VERSION 5.7 ;
  NOWIREEXTENSIONATPIN ON ;
  DIVIDERCHAR "/" ;
  BUSBITCHARS "[]" ;
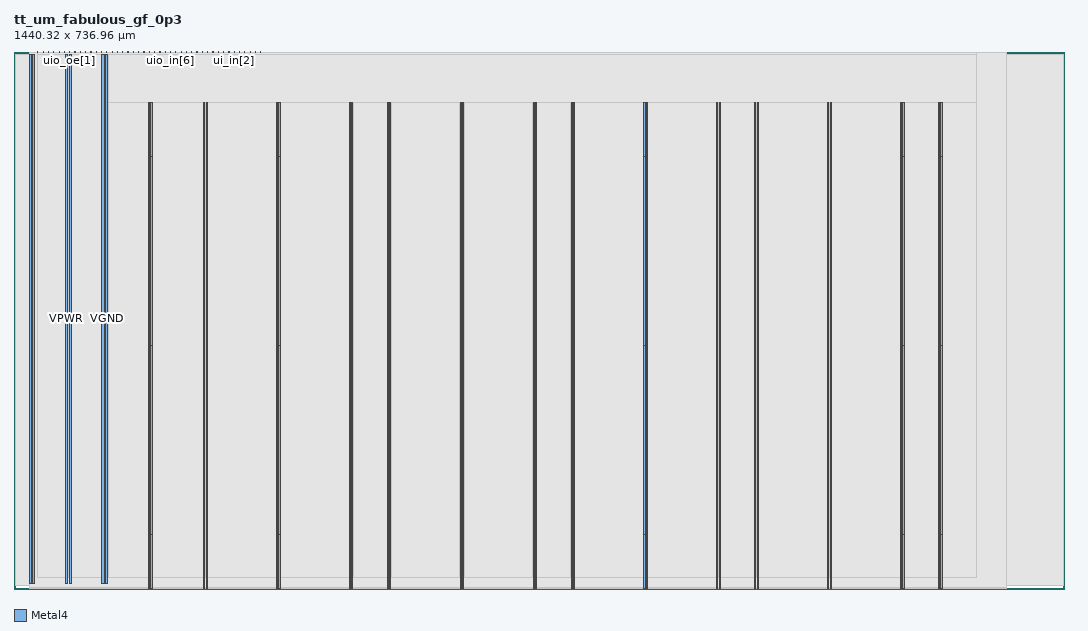
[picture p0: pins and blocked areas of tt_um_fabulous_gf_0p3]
MACRO tt_um_fabulous_gf_0p3
  CLASS BLOCK ;
  FOREIGN tt_um_fabulous_gf_0p3 ;
  ORIGIN 0.000 0.000 ;
  SIZE 1440.320 BY 736.960 ;
  PIN VGND
    DIRECTION INOUT ;
    USE GROUND ;
    PORT
      LAYER Metal4 ;
        RECT 187.780 592.600 189.380 667.080 ;
    END
    PORT
      LAYER Metal4 ;
        RECT 187.780 333.880 189.380 592.600 ;
    END
    PORT
      LAYER Metal4 ;
        RECT 187.780 75.160 189.380 333.880 ;
    END
    PORT
      LAYER Metal4 ;
        RECT 187.780 0.680 189.380 75.160 ;
    END
    PORT
      LAYER Metal4 ;
        RECT 263.380 592.600 264.980 667.080 ;
    END
    PORT
      LAYER Metal4 ;
        RECT 363.380 592.600 364.980 667.080 ;
    END
    PORT
      LAYER Metal4 ;
        RECT 463.380 592.600 464.980 667.080 ;
    END
    PORT
      LAYER Metal4 ;
        RECT 263.380 333.880 264.980 592.600 ;
    END
    PORT
      LAYER Metal4 ;
        RECT 363.380 333.880 364.980 592.600 ;
    END
    PORT
      LAYER Metal4 ;
        RECT 463.380 333.880 464.980 592.600 ;
    END
    PORT
      LAYER Metal4 ;
        RECT 263.380 75.160 264.980 333.880 ;
    END
    PORT
      LAYER Metal4 ;
        RECT 363.380 75.160 364.980 333.880 ;
    END
    PORT
      LAYER Metal4 ;
        RECT 463.380 75.160 464.980 333.880 ;
    END
    PORT
      LAYER Metal4 ;
        RECT 263.380 0.680 264.980 75.160 ;
    END
    PORT
      LAYER Metal4 ;
        RECT 363.380 0.680 364.980 75.160 ;
    END
    PORT
      LAYER Metal4 ;
        RECT 463.380 0.680 464.980 75.160 ;
    END
    PORT
      LAYER Metal4 ;
        RECT 515.380 592.600 516.980 667.080 ;
    END
    PORT
      LAYER Metal4 ;
        RECT 615.380 592.600 616.980 667.080 ;
    END
    PORT
      LAYER Metal4 ;
        RECT 715.380 592.600 716.980 667.080 ;
    END
    PORT
      LAYER Metal4 ;
        RECT 515.380 333.880 516.980 592.600 ;
    END
    PORT
      LAYER Metal4 ;
        RECT 615.380 333.880 616.980 592.600 ;
    END
    PORT
      LAYER Metal4 ;
        RECT 715.380 333.880 716.980 592.600 ;
    END
    PORT
      LAYER Metal4 ;
        RECT 515.380 75.160 516.980 333.880 ;
    END
    PORT
      LAYER Metal4 ;
        RECT 615.380 75.160 616.980 333.880 ;
    END
    PORT
      LAYER Metal4 ;
        RECT 715.380 75.160 716.980 333.880 ;
    END
    PORT
      LAYER Metal4 ;
        RECT 515.380 0.680 516.980 75.160 ;
    END
    PORT
      LAYER Metal4 ;
        RECT 615.380 0.680 616.980 75.160 ;
    END
    PORT
      LAYER Metal4 ;
        RECT 715.380 0.680 716.980 75.160 ;
    END
    PORT
      LAYER Metal4 ;
        RECT 767.380 592.600 768.980 667.080 ;
    END
    PORT
      LAYER Metal4 ;
        RECT 867.380 592.600 868.980 667.080 ;
    END
    PORT
      LAYER Metal4 ;
        RECT 967.380 592.600 968.980 667.080 ;
    END
    PORT
      LAYER Metal4 ;
        RECT 767.380 333.880 768.980 592.600 ;
    END
    PORT
      LAYER Metal4 ;
        RECT 867.380 333.880 868.980 592.600 ;
    END
    PORT
      LAYER Metal4 ;
        RECT 967.380 333.880 968.980 592.600 ;
    END
    PORT
      LAYER Metal4 ;
        RECT 767.380 75.160 768.980 333.880 ;
    END
    PORT
      LAYER Metal4 ;
        RECT 867.380 75.160 868.980 333.880 ;
    END
    PORT
      LAYER Metal4 ;
        RECT 967.380 75.160 968.980 333.880 ;
    END
    PORT
      LAYER Metal4 ;
        RECT 767.380 0.680 768.980 75.160 ;
    END
    PORT
      LAYER Metal4 ;
        RECT 867.380 0.680 868.980 75.160 ;
    END
    PORT
      LAYER Metal4 ;
        RECT 967.380 0.680 968.980 75.160 ;
    END
    PORT
      LAYER Metal4 ;
        RECT 1019.380 592.600 1020.980 667.080 ;
    END
    PORT
      LAYER Metal4 ;
        RECT 1119.380 592.600 1120.980 667.080 ;
    END
    PORT
      LAYER Metal4 ;
        RECT 1219.380 592.600 1220.980 667.080 ;
    END
    PORT
      LAYER Metal4 ;
        RECT 1019.380 333.880 1020.980 592.600 ;
    END
    PORT
      LAYER Metal4 ;
        RECT 1119.380 333.880 1120.980 592.600 ;
    END
    PORT
      LAYER Metal4 ;
        RECT 1219.380 333.880 1220.980 592.600 ;
    END
    PORT
      LAYER Metal4 ;
        RECT 1019.380 75.160 1020.980 333.880 ;
    END
    PORT
      LAYER Metal4 ;
        RECT 1119.380 75.160 1120.980 333.880 ;
    END
    PORT
      LAYER Metal4 ;
        RECT 1219.380 75.160 1220.980 333.880 ;
    END
    PORT
      LAYER Metal4 ;
        RECT 1019.380 0.680 1020.980 75.160 ;
    END
    PORT
      LAYER Metal4 ;
        RECT 1119.380 0.680 1120.980 75.160 ;
    END
    PORT
      LAYER Metal4 ;
        RECT 1219.380 0.680 1220.980 75.160 ;
    END
    PORT
      LAYER Metal4 ;
        RECT 1271.380 592.600 1272.980 667.080 ;
    END
    PORT
      LAYER Metal4 ;
        RECT 1271.380 333.880 1272.980 592.600 ;
    END
    PORT
      LAYER Metal4 ;
        RECT 1271.380 75.160 1272.980 333.880 ;
    END
    PORT
      LAYER Metal4 ;
        RECT 1271.380 0.680 1272.980 75.160 ;
    END
    PORT
      LAYER Metal4 ;
        RECT 25.540 7.540 28.740 733.340 ;
    END
    PORT
      LAYER Metal4 ;
        RECT 75.540 7.540 78.740 733.340 ;
    END
    PORT
      LAYER Metal4 ;
        RECT 125.540 7.540 128.740 733.340 ;
    END
  END VGND
  PIN VPWR
    DIRECTION INOUT ;
    USE POWER ;
    PORT
      LAYER Metal4 ;
        RECT 184.480 592.600 186.080 667.080 ;
    END
    PORT
      LAYER Metal4 ;
        RECT 184.480 333.880 186.080 592.600 ;
    END
    PORT
      LAYER Metal4 ;
        RECT 184.480 75.160 186.080 333.880 ;
    END
    PORT
      LAYER Metal4 ;
        RECT 184.480 0.680 186.080 75.160 ;
    END
    PORT
      LAYER Metal4 ;
        RECT 260.080 592.600 261.680 667.080 ;
    END
    PORT
      LAYER Metal4 ;
        RECT 360.080 592.600 361.680 667.080 ;
    END
    PORT
      LAYER Metal4 ;
        RECT 460.080 592.600 461.680 667.080 ;
    END
    PORT
      LAYER Metal4 ;
        RECT 260.080 333.880 261.680 592.600 ;
    END
    PORT
      LAYER Metal4 ;
        RECT 360.080 333.880 361.680 592.600 ;
    END
    PORT
      LAYER Metal4 ;
        RECT 460.080 333.880 461.680 592.600 ;
    END
    PORT
      LAYER Metal4 ;
        RECT 260.080 75.160 261.680 333.880 ;
    END
    PORT
      LAYER Metal4 ;
        RECT 360.080 75.160 361.680 333.880 ;
    END
    PORT
      LAYER Metal4 ;
        RECT 460.080 75.160 461.680 333.880 ;
    END
    PORT
      LAYER Metal4 ;
        RECT 260.080 0.680 261.680 75.160 ;
    END
    PORT
      LAYER Metal4 ;
        RECT 360.080 0.680 361.680 75.160 ;
    END
    PORT
      LAYER Metal4 ;
        RECT 460.080 0.680 461.680 75.160 ;
    END
    PORT
      LAYER Metal4 ;
        RECT 512.080 592.600 513.680 667.080 ;
    END
    PORT
      LAYER Metal4 ;
        RECT 612.080 592.600 613.680 667.080 ;
    END
    PORT
      LAYER Metal4 ;
        RECT 712.080 592.600 713.680 667.080 ;
    END
    PORT
      LAYER Metal4 ;
        RECT 512.080 333.880 513.680 592.600 ;
    END
    PORT
      LAYER Metal4 ;
        RECT 612.080 333.880 613.680 592.600 ;
    END
    PORT
      LAYER Metal4 ;
        RECT 712.080 333.880 713.680 592.600 ;
    END
    PORT
      LAYER Metal4 ;
        RECT 512.080 75.160 513.680 333.880 ;
    END
    PORT
      LAYER Metal4 ;
        RECT 612.080 75.160 613.680 333.880 ;
    END
    PORT
      LAYER Metal4 ;
        RECT 712.080 75.160 713.680 333.880 ;
    END
    PORT
      LAYER Metal4 ;
        RECT 512.080 0.680 513.680 75.160 ;
    END
    PORT
      LAYER Metal4 ;
        RECT 612.080 0.680 613.680 75.160 ;
    END
    PORT
      LAYER Metal4 ;
        RECT 712.080 0.680 713.680 75.160 ;
    END
    PORT
      LAYER Metal4 ;
        RECT 764.080 592.600 765.680 667.080 ;
    END
    PORT
      LAYER Metal4 ;
        RECT 864.080 592.600 865.680 667.080 ;
    END
    PORT
      LAYER Metal4 ;
        RECT 964.080 592.600 965.680 667.080 ;
    END
    PORT
      LAYER Metal4 ;
        RECT 764.080 333.880 765.680 592.600 ;
    END
    PORT
      LAYER Metal4 ;
        RECT 864.080 333.880 865.680 592.600 ;
    END
    PORT
      LAYER Metal4 ;
        RECT 964.080 333.880 965.680 592.600 ;
    END
    PORT
      LAYER Metal4 ;
        RECT 764.080 75.160 765.680 333.880 ;
    END
    PORT
      LAYER Metal4 ;
        RECT 864.080 75.160 865.680 333.880 ;
    END
    PORT
      LAYER Metal4 ;
        RECT 964.080 75.160 965.680 333.880 ;
    END
    PORT
      LAYER Metal4 ;
        RECT 764.080 0.680 765.680 75.160 ;
    END
    PORT
      LAYER Metal4 ;
        RECT 864.080 0.680 865.680 75.160 ;
    END
    PORT
      LAYER Metal4 ;
        RECT 964.080 0.680 965.680 75.160 ;
    END
    PORT
      LAYER Metal4 ;
        RECT 1016.080 592.600 1017.680 667.080 ;
    END
    PORT
      LAYER Metal4 ;
        RECT 1116.080 592.600 1117.680 667.080 ;
    END
    PORT
      LAYER Metal4 ;
        RECT 1216.080 592.600 1217.680 667.080 ;
    END
    PORT
      LAYER Metal4 ;
        RECT 1016.080 333.880 1017.680 592.600 ;
    END
    PORT
      LAYER Metal4 ;
        RECT 1116.080 333.880 1117.680 592.600 ;
    END
    PORT
      LAYER Metal4 ;
        RECT 1216.080 333.880 1217.680 592.600 ;
    END
    PORT
      LAYER Metal4 ;
        RECT 1016.080 75.160 1017.680 333.880 ;
    END
    PORT
      LAYER Metal4 ;
        RECT 1116.080 75.160 1117.680 333.880 ;
    END
    PORT
      LAYER Metal4 ;
        RECT 1216.080 75.160 1217.680 333.880 ;
    END
    PORT
      LAYER Metal4 ;
        RECT 1016.080 0.680 1017.680 75.160 ;
    END
    PORT
      LAYER Metal4 ;
        RECT 1116.080 0.680 1117.680 75.160 ;
    END
    PORT
      LAYER Metal4 ;
        RECT 1216.080 0.680 1217.680 75.160 ;
    END
    PORT
      LAYER Metal4 ;
        RECT 1268.080 592.600 1269.680 667.080 ;
    END
    PORT
      LAYER Metal4 ;
        RECT 1268.080 333.880 1269.680 592.600 ;
    END
    PORT
      LAYER Metal4 ;
        RECT 1268.080 75.160 1269.680 333.880 ;
    END
    PORT
      LAYER Metal4 ;
        RECT 1268.080 0.680 1269.680 75.160 ;
    END
    PORT
      LAYER Metal4 ;
        RECT 20.640 7.540 23.840 733.340 ;
    END
    PORT
      LAYER Metal4 ;
        RECT 70.640 7.540 73.840 733.340 ;
    END
    PORT
      LAYER Metal4 ;
        RECT 120.640 7.540 123.840 733.340 ;
    END
  END VPWR
  PIN clk
    DIRECTION INPUT ;
    USE SIGNAL ;
    ANTENNAGATEAREA 9.476000 ;
    ANTENNADIFFAREA 0.820800 ;
    PORT
      LAYER Metal4 ;
        RECT 331.090 735.960 331.390 736.960 ;
    END
  END clk
  PIN ena
    DIRECTION INPUT ;
    USE SIGNAL ;
    PORT
      LAYER Metal4 ;
        RECT 338.370 735.960 338.670 736.960 ;
    END
  END ena
  PIN rst_n
    DIRECTION INPUT ;
    USE SIGNAL ;
    ANTENNAGATEAREA 0.396000 ;
    ANTENNADIFFAREA 0.410400 ;
    PORT
      LAYER Metal4 ;
        RECT 323.810 735.960 324.110 736.960 ;
    END
  END rst_n
  PIN ui_in[0]
    DIRECTION INPUT ;
    USE SIGNAL ;
    ANTENNAGATEAREA 0.396000 ;
    ANTENNADIFFAREA 0.410400 ;
    PORT
      LAYER Metal4 ;
        RECT 316.530 735.960 316.830 736.960 ;
    END
  END ui_in[0]
  PIN ui_in[1]
    DIRECTION INPUT ;
    USE SIGNAL ;
    ANTENNAGATEAREA 0.396000 ;
    ANTENNADIFFAREA 0.410400 ;
    PORT
      LAYER Metal4 ;
        RECT 309.250 735.960 309.550 736.960 ;
    END
  END ui_in[1]
  PIN ui_in[2]
    DIRECTION INPUT ;
    USE SIGNAL ;
    ANTENNAGATEAREA 1.498000 ;
    ANTENNADIFFAREA 0.410400 ;
    PORT
      LAYER Metal4 ;
        RECT 301.970 735.960 302.270 736.960 ;
    END
  END ui_in[2]
  PIN ui_in[3]
    DIRECTION INPUT ;
    USE SIGNAL ;
    ANTENNAGATEAREA 1.498000 ;
    ANTENNADIFFAREA 0.410400 ;
    PORT
      LAYER Metal4 ;
        RECT 294.690 735.960 294.990 736.960 ;
    END
  END ui_in[3]
  PIN ui_in[4]
    DIRECTION INPUT ;
    USE SIGNAL ;
    ANTENNAGATEAREA 1.498000 ;
    ANTENNADIFFAREA 0.410400 ;
    PORT
      LAYER Metal4 ;
        RECT 287.410 735.960 287.710 736.960 ;
    END
  END ui_in[4]
  PIN ui_in[5]
    DIRECTION INPUT ;
    USE SIGNAL ;
    ANTENNAGATEAREA 1.498000 ;
    ANTENNADIFFAREA 0.410400 ;
    PORT
      LAYER Metal4 ;
        RECT 280.130 735.960 280.430 736.960 ;
    END
  END ui_in[5]
  PIN ui_in[6]
    DIRECTION INPUT ;
    USE SIGNAL ;
    ANTENNAGATEAREA 1.498000 ;
    ANTENNADIFFAREA 0.410400 ;
    PORT
      LAYER Metal4 ;
        RECT 272.850 735.960 273.150 736.960 ;
    END
  END ui_in[6]
  PIN ui_in[7]
    DIRECTION INPUT ;
    USE SIGNAL ;
    ANTENNAGATEAREA 1.498000 ;
    ANTENNADIFFAREA 0.410400 ;
    PORT
      LAYER Metal4 ;
        RECT 265.570 735.960 265.870 736.960 ;
    END
  END ui_in[7]
  PIN uio_in[0]
    DIRECTION INPUT ;
    USE SIGNAL ;
    ANTENNAGATEAREA 1.498000 ;
    ANTENNADIFFAREA 0.410400 ;
    PORT
      LAYER Metal4 ;
        RECT 258.290 735.960 258.590 736.960 ;
    END
  END uio_in[0]
  PIN uio_in[1]
    DIRECTION INPUT ;
    USE SIGNAL ;
    ANTENNAGATEAREA 1.498000 ;
    ANTENNADIFFAREA 0.410400 ;
    PORT
      LAYER Metal4 ;
        RECT 251.010 735.960 251.310 736.960 ;
    END
  END uio_in[1]
  PIN uio_in[2]
    DIRECTION INPUT ;
    USE SIGNAL ;
    ANTENNAGATEAREA 2.597500 ;
    ANTENNADIFFAREA 0.410400 ;
    PORT
      LAYER Metal4 ;
        RECT 243.730 735.960 244.030 736.960 ;
    END
  END uio_in[2]
  PIN uio_in[3]
    DIRECTION INPUT ;
    USE SIGNAL ;
    ANTENNAGATEAREA 1.498000 ;
    ANTENNADIFFAREA 0.410400 ;
    PORT
      LAYER Metal4 ;
        RECT 236.450 735.960 236.750 736.960 ;
    END
  END uio_in[3]
  PIN uio_in[4]
    DIRECTION INPUT ;
    USE SIGNAL ;
    ANTENNAGATEAREA 1.498000 ;
    ANTENNADIFFAREA 0.410400 ;
    PORT
      LAYER Metal4 ;
        RECT 229.170 735.960 229.470 736.960 ;
    END
  END uio_in[4]
  PIN uio_in[5]
    DIRECTION INPUT ;
    USE SIGNAL ;
    ANTENNAGATEAREA 1.498000 ;
    ANTENNADIFFAREA 0.410400 ;
    PORT
      LAYER Metal4 ;
        RECT 221.890 735.960 222.190 736.960 ;
    END
  END uio_in[5]
  PIN uio_in[6]
    DIRECTION INPUT ;
    USE SIGNAL ;
    ANTENNAGATEAREA 2.597500 ;
    ANTENNADIFFAREA 0.410400 ;
    PORT
      LAYER Metal4 ;
        RECT 214.610 735.960 214.910 736.960 ;
    END
  END uio_in[6]
  PIN uio_in[7]
    DIRECTION INPUT ;
    USE SIGNAL ;
    ANTENNAGATEAREA 1.498000 ;
    ANTENNADIFFAREA 0.820800 ;
    PORT
      LAYER Metal4 ;
        RECT 207.330 735.960 207.630 736.960 ;
    END
  END uio_in[7]
  PIN uio_oe[0]
    DIRECTION OUTPUT ;
    USE SIGNAL ;
    ANTENNADIFFAREA 1.308000 ;
    PORT
      LAYER Metal4 ;
        RECT 83.570 735.960 83.870 736.960 ;
    END
  END uio_oe[0]
  PIN uio_oe[1]
    DIRECTION OUTPUT ;
    USE SIGNAL ;
    ANTENNADIFFAREA 1.308000 ;
    PORT
      LAYER Metal4 ;
        RECT 76.290 735.960 76.590 736.960 ;
    END
  END uio_oe[1]
  PIN uio_oe[2]
    DIRECTION OUTPUT ;
    USE SIGNAL ;
    ANTENNADIFFAREA 1.308000 ;
    PORT
      LAYER Metal4 ;
        RECT 69.010 735.960 69.310 736.960 ;
    END
  END uio_oe[2]
  PIN uio_oe[3]
    DIRECTION OUTPUT ;
    USE SIGNAL ;
    ANTENNADIFFAREA 1.308000 ;
    PORT
      LAYER Metal4 ;
        RECT 61.730 735.960 62.030 736.960 ;
    END
  END uio_oe[3]
  PIN uio_oe[4]
    DIRECTION OUTPUT ;
    USE SIGNAL ;
    ANTENNADIFFAREA 1.308000 ;
    PORT
      LAYER Metal4 ;
        RECT 54.450 735.960 54.750 736.960 ;
    END
  END uio_oe[4]
  PIN uio_oe[5]
    DIRECTION OUTPUT ;
    USE SIGNAL ;
    ANTENNADIFFAREA 1.308000 ;
    PORT
      LAYER Metal4 ;
        RECT 47.170 735.960 47.470 736.960 ;
    END
  END uio_oe[5]
  PIN uio_oe[6]
    DIRECTION OUTPUT ;
    USE SIGNAL ;
    ANTENNADIFFAREA 1.308000 ;
    PORT
      LAYER Metal4 ;
        RECT 39.890 735.960 40.190 736.960 ;
    END
  END uio_oe[6]
  PIN uio_oe[7]
    DIRECTION OUTPUT ;
    USE SIGNAL ;
    ANTENNADIFFAREA 1.308000 ;
    PORT
      LAYER Metal4 ;
        RECT 32.610 735.960 32.910 736.960 ;
    END
  END uio_oe[7]
  PIN uio_out[0]
    DIRECTION OUTPUT ;
    USE SIGNAL ;
    ANTENNADIFFAREA 1.308000 ;
    PORT
      LAYER Metal4 ;
        RECT 141.810 735.960 142.110 736.960 ;
    END
  END uio_out[0]
  PIN uio_out[1]
    DIRECTION OUTPUT ;
    USE SIGNAL ;
    ANTENNADIFFAREA 1.308000 ;
    PORT
      LAYER Metal4 ;
        RECT 134.530 735.960 134.830 736.960 ;
    END
  END uio_out[1]
  PIN uio_out[2]
    DIRECTION OUTPUT ;
    USE SIGNAL ;
    ANTENNADIFFAREA 1.308000 ;
    PORT
      LAYER Metal4 ;
        RECT 127.250 735.960 127.550 736.960 ;
    END
  END uio_out[2]
  PIN uio_out[3]
    DIRECTION OUTPUT ;
    USE SIGNAL ;
    ANTENNADIFFAREA 1.308000 ;
    PORT
      LAYER Metal4 ;
        RECT 119.970 735.960 120.270 736.960 ;
    END
  END uio_out[3]
  PIN uio_out[4]
    DIRECTION OUTPUT ;
    USE SIGNAL ;
    ANTENNADIFFAREA 1.308000 ;
    PORT
      LAYER Metal4 ;
        RECT 112.690 735.960 112.990 736.960 ;
    END
  END uio_out[4]
  PIN uio_out[5]
    DIRECTION OUTPUT ;
    USE SIGNAL ;
    ANTENNADIFFAREA 1.308000 ;
    PORT
      LAYER Metal4 ;
        RECT 105.410 735.960 105.710 736.960 ;
    END
  END uio_out[5]
  PIN uio_out[6]
    DIRECTION OUTPUT ;
    USE SIGNAL ;
    ANTENNADIFFAREA 1.308000 ;
    PORT
      LAYER Metal4 ;
        RECT 98.130 735.960 98.430 736.960 ;
    END
  END uio_out[6]
  PIN uio_out[7]
    DIRECTION OUTPUT ;
    USE SIGNAL ;
    ANTENNADIFFAREA 1.308000 ;
    PORT
      LAYER Metal4 ;
        RECT 90.850 735.960 91.150 736.960 ;
    END
  END uio_out[7]
  PIN uo_out[0]
    DIRECTION OUTPUT ;
    USE SIGNAL ;
    ANTENNADIFFAREA 2.776000 ;
    PORT
      LAYER Metal4 ;
        RECT 200.050 735.960 200.350 736.960 ;
    END
  END uo_out[0]
  PIN uo_out[1]
    DIRECTION OUTPUT ;
    USE SIGNAL ;
    ANTENNADIFFAREA 2.776000 ;
    PORT
      LAYER Metal4 ;
        RECT 192.770 735.960 193.070 736.960 ;
    END
  END uo_out[1]
  PIN uo_out[2]
    DIRECTION OUTPUT ;
    USE SIGNAL ;
    ANTENNADIFFAREA 5.141600 ;
    PORT
      LAYER Metal4 ;
        RECT 185.490 735.960 185.790 736.960 ;
    END
  END uo_out[2]
  PIN uo_out[3]
    DIRECTION OUTPUT ;
    USE SIGNAL ;
    ANTENNADIFFAREA 5.141600 ;
    PORT
      LAYER Metal4 ;
        RECT 178.210 735.960 178.510 736.960 ;
    END
  END uo_out[3]
  PIN uo_out[4]
    DIRECTION OUTPUT ;
    USE SIGNAL ;
    ANTENNADIFFAREA 5.141600 ;
    PORT
      LAYER Metal4 ;
        RECT 170.930 735.960 171.230 736.960 ;
    END
  END uo_out[4]
  PIN uo_out[5]
    DIRECTION OUTPUT ;
    USE SIGNAL ;
    ANTENNADIFFAREA 5.141600 ;
    PORT
      LAYER Metal4 ;
        RECT 163.650 735.960 163.950 736.960 ;
    END
  END uo_out[5]
  PIN uo_out[6]
    DIRECTION OUTPUT ;
    USE SIGNAL ;
    ANTENNADIFFAREA 5.141600 ;
    PORT
      LAYER Metal4 ;
        RECT 156.370 735.960 156.670 736.960 ;
    END
  END uo_out[6]
  PIN uo_out[7]
    DIRECTION OUTPUT ;
    USE SIGNAL ;
    ANTENNADIFFAREA 5.141600 ;
    PORT
      LAYER Metal4 ;
        RECT 149.090 735.960 149.390 736.960 ;
    END
  END uo_out[7]
  OBS
      LAYER Nwell ;
        RECT 1.810 730.880 1440.190 733.470 ;
      LAYER Pwell ;
        RECT 1.810 727.360 1440.190 730.880 ;
      LAYER Nwell ;
        RECT 1.810 723.040 1440.190 727.360 ;
      LAYER Pwell ;
        RECT 1.810 719.520 1440.190 723.040 ;
      LAYER Nwell ;
        RECT 1.810 715.200 1440.190 719.520 ;
      LAYER Pwell ;
        RECT 1.810 711.680 1440.190 715.200 ;
      LAYER Nwell ;
        RECT 1.810 707.360 1440.190 711.680 ;
      LAYER Pwell ;
        RECT 1.810 703.840 1440.190 707.360 ;
      LAYER Nwell ;
        RECT 1.810 699.520 1440.190 703.840 ;
      LAYER Pwell ;
        RECT 1.810 696.000 1440.190 699.520 ;
      LAYER Nwell ;
        RECT 1.810 691.680 1440.190 696.000 ;
      LAYER Pwell ;
        RECT 1.810 688.160 1440.190 691.680 ;
      LAYER Nwell ;
        RECT 1.810 683.840 1440.190 688.160 ;
      LAYER Pwell ;
        RECT 1.810 680.320 1440.190 683.840 ;
      LAYER Nwell ;
        RECT 1.810 676.000 1440.190 680.320 ;
      LAYER Pwell ;
        RECT 1.810 673.810 1440.190 676.000 ;
        RECT 1.810 672.480 161.150 673.810 ;
      LAYER Nwell ;
        RECT 161.150 672.480 1440.190 673.810 ;
        RECT 1.810 668.160 1440.190 672.480 ;
      LAYER Pwell ;
        RECT 1.810 664.640 161.150 668.160 ;
      LAYER Nwell ;
        RECT 161.150 664.640 1440.190 668.160 ;
        RECT 1.810 660.320 1440.190 664.640 ;
      LAYER Pwell ;
        RECT 1.810 656.800 161.150 660.320 ;
      LAYER Nwell ;
        RECT 161.150 656.800 1440.190 660.320 ;
        RECT 1.810 652.480 1440.190 656.800 ;
      LAYER Pwell ;
        RECT 1.810 648.960 161.150 652.480 ;
      LAYER Nwell ;
        RECT 161.150 648.960 1440.190 652.480 ;
        RECT 1.810 644.640 1440.190 648.960 ;
      LAYER Pwell ;
        RECT 1.810 641.120 161.150 644.640 ;
      LAYER Nwell ;
        RECT 161.150 641.120 1440.190 644.640 ;
        RECT 1.810 636.800 1440.190 641.120 ;
      LAYER Pwell ;
        RECT 1.810 633.280 161.150 636.800 ;
      LAYER Nwell ;
        RECT 161.150 633.280 1440.190 636.800 ;
        RECT 1.810 628.960 1440.190 633.280 ;
      LAYER Pwell ;
        RECT 1.810 625.440 161.150 628.960 ;
      LAYER Nwell ;
        RECT 161.150 625.440 1440.190 628.960 ;
        RECT 1.810 621.120 1440.190 625.440 ;
      LAYER Pwell ;
        RECT 1.810 617.600 161.150 621.120 ;
      LAYER Nwell ;
        RECT 161.150 617.600 1440.190 621.120 ;
        RECT 1.810 613.280 1440.190 617.600 ;
      LAYER Pwell ;
        RECT 1.810 609.760 161.150 613.280 ;
      LAYER Nwell ;
        RECT 161.150 609.760 1440.190 613.280 ;
        RECT 1.810 605.440 1440.190 609.760 ;
      LAYER Pwell ;
        RECT 1.810 601.920 161.150 605.440 ;
      LAYER Nwell ;
        RECT 161.150 601.920 1440.190 605.440 ;
        RECT 1.810 597.600 1440.190 601.920 ;
      LAYER Pwell ;
        RECT 1.810 594.080 161.150 597.600 ;
      LAYER Nwell ;
        RECT 161.150 594.080 1440.190 597.600 ;
        RECT 1.810 589.760 1440.190 594.080 ;
      LAYER Pwell ;
        RECT 1.810 586.240 161.150 589.760 ;
      LAYER Nwell ;
        RECT 161.150 586.240 1440.190 589.760 ;
        RECT 1.810 581.920 1440.190 586.240 ;
      LAYER Pwell ;
        RECT 1.810 578.400 161.150 581.920 ;
      LAYER Nwell ;
        RECT 161.150 578.400 1440.190 581.920 ;
        RECT 1.810 574.080 1440.190 578.400 ;
      LAYER Pwell ;
        RECT 1.810 570.560 161.150 574.080 ;
      LAYER Nwell ;
        RECT 161.150 570.560 1440.190 574.080 ;
        RECT 1.810 566.240 1440.190 570.560 ;
      LAYER Pwell ;
        RECT 1.810 562.720 161.150 566.240 ;
      LAYER Nwell ;
        RECT 161.150 562.720 1440.190 566.240 ;
        RECT 1.810 558.400 1440.190 562.720 ;
      LAYER Pwell ;
        RECT 1.810 554.880 161.150 558.400 ;
      LAYER Nwell ;
        RECT 161.150 554.880 1440.190 558.400 ;
        RECT 1.810 550.560 1440.190 554.880 ;
      LAYER Pwell ;
        RECT 1.810 547.040 161.150 550.560 ;
      LAYER Nwell ;
        RECT 161.150 547.040 1440.190 550.560 ;
        RECT 1.810 542.720 1440.190 547.040 ;
      LAYER Pwell ;
        RECT 1.810 539.200 161.150 542.720 ;
      LAYER Nwell ;
        RECT 161.150 539.200 1440.190 542.720 ;
        RECT 1.810 534.880 1440.190 539.200 ;
      LAYER Pwell ;
        RECT 1.810 531.360 161.150 534.880 ;
      LAYER Nwell ;
        RECT 161.150 531.360 1440.190 534.880 ;
        RECT 1.810 527.040 1440.190 531.360 ;
      LAYER Pwell ;
        RECT 1.810 523.520 161.150 527.040 ;
      LAYER Nwell ;
        RECT 161.150 523.520 1440.190 527.040 ;
        RECT 1.810 519.200 1440.190 523.520 ;
      LAYER Pwell ;
        RECT 1.810 515.680 161.150 519.200 ;
      LAYER Nwell ;
        RECT 161.150 515.680 1440.190 519.200 ;
        RECT 1.810 511.360 1440.190 515.680 ;
      LAYER Pwell ;
        RECT 1.810 507.840 161.150 511.360 ;
      LAYER Nwell ;
        RECT 161.150 507.840 1440.190 511.360 ;
        RECT 1.810 503.520 1440.190 507.840 ;
      LAYER Pwell ;
        RECT 1.810 500.000 161.150 503.520 ;
      LAYER Nwell ;
        RECT 161.150 500.000 1440.190 503.520 ;
        RECT 1.810 495.680 1440.190 500.000 ;
      LAYER Pwell ;
        RECT 1.810 492.160 161.150 495.680 ;
      LAYER Nwell ;
        RECT 161.150 492.160 1440.190 495.680 ;
        RECT 1.810 487.840 1440.190 492.160 ;
      LAYER Pwell ;
        RECT 1.810 484.320 161.150 487.840 ;
      LAYER Nwell ;
        RECT 161.150 484.320 1440.190 487.840 ;
        RECT 1.810 480.000 1440.190 484.320 ;
      LAYER Pwell ;
        RECT 1.810 476.480 161.150 480.000 ;
      LAYER Nwell ;
        RECT 161.150 476.480 1440.190 480.000 ;
        RECT 1.810 472.160 1440.190 476.480 ;
      LAYER Pwell ;
        RECT 1.810 468.640 161.150 472.160 ;
      LAYER Nwell ;
        RECT 161.150 468.640 1440.190 472.160 ;
        RECT 1.810 464.320 1440.190 468.640 ;
      LAYER Pwell ;
        RECT 1.810 460.800 161.150 464.320 ;
      LAYER Nwell ;
        RECT 161.150 460.800 1440.190 464.320 ;
        RECT 1.810 456.480 1440.190 460.800 ;
      LAYER Pwell ;
        RECT 1.810 452.960 161.150 456.480 ;
      LAYER Nwell ;
        RECT 161.150 452.960 1440.190 456.480 ;
        RECT 1.810 448.640 1440.190 452.960 ;
      LAYER Pwell ;
        RECT 1.810 445.120 161.150 448.640 ;
      LAYER Nwell ;
        RECT 161.150 445.120 1440.190 448.640 ;
        RECT 1.810 440.800 1440.190 445.120 ;
      LAYER Pwell ;
        RECT 1.810 437.280 161.150 440.800 ;
      LAYER Nwell ;
        RECT 161.150 437.280 1440.190 440.800 ;
        RECT 1.810 432.960 1440.190 437.280 ;
      LAYER Pwell ;
        RECT 1.810 429.440 161.150 432.960 ;
      LAYER Nwell ;
        RECT 161.150 429.440 1440.190 432.960 ;
        RECT 1.810 425.120 1440.190 429.440 ;
      LAYER Pwell ;
        RECT 1.810 421.600 161.150 425.120 ;
      LAYER Nwell ;
        RECT 161.150 421.600 1440.190 425.120 ;
        RECT 1.810 417.280 1440.190 421.600 ;
      LAYER Pwell ;
        RECT 1.810 413.760 161.150 417.280 ;
      LAYER Nwell ;
        RECT 161.150 413.760 1440.190 417.280 ;
        RECT 1.810 409.440 1440.190 413.760 ;
      LAYER Pwell ;
        RECT 1.810 405.920 161.150 409.440 ;
      LAYER Nwell ;
        RECT 161.150 405.920 1440.190 409.440 ;
        RECT 1.810 401.600 1440.190 405.920 ;
      LAYER Pwell ;
        RECT 1.810 398.080 161.150 401.600 ;
      LAYER Nwell ;
        RECT 161.150 398.080 1440.190 401.600 ;
        RECT 1.810 393.760 1440.190 398.080 ;
      LAYER Pwell ;
        RECT 1.810 390.240 161.150 393.760 ;
      LAYER Nwell ;
        RECT 161.150 390.240 1440.190 393.760 ;
        RECT 1.810 385.920 1440.190 390.240 ;
      LAYER Pwell ;
        RECT 1.810 382.400 161.150 385.920 ;
      LAYER Nwell ;
        RECT 161.150 382.400 1440.190 385.920 ;
        RECT 1.810 378.080 1440.190 382.400 ;
      LAYER Pwell ;
        RECT 1.810 374.560 161.150 378.080 ;
      LAYER Nwell ;
        RECT 161.150 374.560 1440.190 378.080 ;
        RECT 1.810 370.240 1440.190 374.560 ;
      LAYER Pwell ;
        RECT 1.810 366.720 161.150 370.240 ;
      LAYER Nwell ;
        RECT 161.150 366.720 1440.190 370.240 ;
        RECT 1.810 362.400 1440.190 366.720 ;
      LAYER Pwell ;
        RECT 1.810 358.880 161.150 362.400 ;
      LAYER Nwell ;
        RECT 161.150 358.880 1440.190 362.400 ;
        RECT 1.810 354.560 1440.190 358.880 ;
      LAYER Pwell ;
        RECT 1.810 351.040 161.150 354.560 ;
      LAYER Nwell ;
        RECT 161.150 351.040 1440.190 354.560 ;
        RECT 1.810 346.720 1440.190 351.040 ;
      LAYER Pwell ;
        RECT 1.810 343.200 161.150 346.720 ;
      LAYER Nwell ;
        RECT 161.150 343.200 1440.190 346.720 ;
        RECT 1.810 338.880 1440.190 343.200 ;
      LAYER Pwell ;
        RECT 1.810 335.360 161.150 338.880 ;
      LAYER Nwell ;
        RECT 161.150 335.360 1440.190 338.880 ;
        RECT 1.810 331.040 1440.190 335.360 ;
      LAYER Pwell ;
        RECT 1.810 327.520 161.150 331.040 ;
      LAYER Nwell ;
        RECT 161.150 327.520 1440.190 331.040 ;
        RECT 1.810 323.200 1440.190 327.520 ;
      LAYER Pwell ;
        RECT 1.810 319.680 161.150 323.200 ;
      LAYER Nwell ;
        RECT 161.150 319.680 1440.190 323.200 ;
        RECT 1.810 315.360 1440.190 319.680 ;
      LAYER Pwell ;
        RECT 1.810 311.840 161.150 315.360 ;
      LAYER Nwell ;
        RECT 161.150 311.840 1440.190 315.360 ;
        RECT 1.810 307.520 1440.190 311.840 ;
      LAYER Pwell ;
        RECT 1.810 304.000 161.150 307.520 ;
      LAYER Nwell ;
        RECT 161.150 304.000 1440.190 307.520 ;
        RECT 1.810 299.680 1440.190 304.000 ;
      LAYER Pwell ;
        RECT 1.810 296.160 161.150 299.680 ;
      LAYER Nwell ;
        RECT 161.150 296.160 1440.190 299.680 ;
        RECT 1.810 291.840 1440.190 296.160 ;
      LAYER Pwell ;
        RECT 1.810 288.320 161.150 291.840 ;
      LAYER Nwell ;
        RECT 161.150 288.320 1440.190 291.840 ;
        RECT 1.810 284.000 1440.190 288.320 ;
      LAYER Pwell ;
        RECT 1.810 280.480 161.150 284.000 ;
      LAYER Nwell ;
        RECT 161.150 280.480 1440.190 284.000 ;
        RECT 1.810 276.160 1440.190 280.480 ;
      LAYER Pwell ;
        RECT 1.810 272.640 161.150 276.160 ;
      LAYER Nwell ;
        RECT 161.150 272.640 1440.190 276.160 ;
        RECT 1.810 268.320 1440.190 272.640 ;
      LAYER Pwell ;
        RECT 1.810 264.800 161.150 268.320 ;
      LAYER Nwell ;
        RECT 161.150 264.800 1440.190 268.320 ;
        RECT 1.810 260.480 1440.190 264.800 ;
      LAYER Pwell ;
        RECT 1.810 256.960 161.150 260.480 ;
      LAYER Nwell ;
        RECT 161.150 256.960 1440.190 260.480 ;
        RECT 1.810 252.640 1440.190 256.960 ;
      LAYER Pwell ;
        RECT 1.810 249.120 161.150 252.640 ;
      LAYER Nwell ;
        RECT 161.150 249.120 1440.190 252.640 ;
        RECT 1.810 244.800 1440.190 249.120 ;
      LAYER Pwell ;
        RECT 1.810 241.280 161.150 244.800 ;
      LAYER Nwell ;
        RECT 161.150 241.280 1440.190 244.800 ;
        RECT 1.810 236.960 1440.190 241.280 ;
      LAYER Pwell ;
        RECT 1.810 233.440 161.150 236.960 ;
      LAYER Nwell ;
        RECT 161.150 233.440 1440.190 236.960 ;
        RECT 1.810 229.120 1440.190 233.440 ;
      LAYER Pwell ;
        RECT 1.810 225.600 161.150 229.120 ;
      LAYER Nwell ;
        RECT 161.150 225.600 1440.190 229.120 ;
        RECT 1.810 221.280 1440.190 225.600 ;
      LAYER Pwell ;
        RECT 1.810 217.760 161.150 221.280 ;
      LAYER Nwell ;
        RECT 161.150 217.760 1440.190 221.280 ;
        RECT 1.810 213.440 1440.190 217.760 ;
      LAYER Pwell ;
        RECT 1.810 209.920 161.150 213.440 ;
      LAYER Nwell ;
        RECT 161.150 209.920 1440.190 213.440 ;
        RECT 1.810 205.600 1440.190 209.920 ;
      LAYER Pwell ;
        RECT 1.810 202.080 161.150 205.600 ;
      LAYER Nwell ;
        RECT 161.150 202.080 1440.190 205.600 ;
        RECT 1.810 197.760 1440.190 202.080 ;
      LAYER Pwell ;
        RECT 1.810 194.240 161.150 197.760 ;
      LAYER Nwell ;
        RECT 161.150 194.240 1440.190 197.760 ;
        RECT 1.810 189.920 1440.190 194.240 ;
      LAYER Pwell ;
        RECT 1.810 186.400 161.150 189.920 ;
      LAYER Nwell ;
        RECT 161.150 186.400 1440.190 189.920 ;
        RECT 1.810 182.080 1440.190 186.400 ;
      LAYER Pwell ;
        RECT 1.810 178.560 161.150 182.080 ;
      LAYER Nwell ;
        RECT 161.150 178.560 1440.190 182.080 ;
        RECT 1.810 174.240 1440.190 178.560 ;
      LAYER Pwell ;
        RECT 1.810 170.720 161.150 174.240 ;
      LAYER Nwell ;
        RECT 161.150 170.720 1440.190 174.240 ;
        RECT 1.810 166.400 1440.190 170.720 ;
      LAYER Pwell ;
        RECT 1.810 162.880 161.150 166.400 ;
      LAYER Nwell ;
        RECT 161.150 162.880 1440.190 166.400 ;
        RECT 1.810 158.560 1440.190 162.880 ;
      LAYER Pwell ;
        RECT 1.810 155.040 161.150 158.560 ;
      LAYER Nwell ;
        RECT 161.150 155.040 1440.190 158.560 ;
        RECT 1.810 150.720 1440.190 155.040 ;
      LAYER Pwell ;
        RECT 1.810 147.200 161.150 150.720 ;
      LAYER Nwell ;
        RECT 161.150 147.200 1440.190 150.720 ;
        RECT 1.810 142.880 1440.190 147.200 ;
      LAYER Pwell ;
        RECT 1.810 139.360 161.150 142.880 ;
      LAYER Nwell ;
        RECT 161.150 139.360 1440.190 142.880 ;
        RECT 1.810 135.040 1440.190 139.360 ;
      LAYER Pwell ;
        RECT 1.810 131.520 161.150 135.040 ;
      LAYER Nwell ;
        RECT 161.150 131.520 1440.190 135.040 ;
        RECT 1.810 127.200 1440.190 131.520 ;
      LAYER Pwell ;
        RECT 1.810 123.680 161.150 127.200 ;
      LAYER Nwell ;
        RECT 161.150 123.680 1440.190 127.200 ;
        RECT 1.810 119.360 1440.190 123.680 ;
      LAYER Pwell ;
        RECT 1.810 115.840 161.150 119.360 ;
      LAYER Nwell ;
        RECT 161.150 115.840 1440.190 119.360 ;
        RECT 1.810 111.520 1440.190 115.840 ;
      LAYER Pwell ;
        RECT 1.810 108.000 161.150 111.520 ;
      LAYER Nwell ;
        RECT 161.150 108.000 1440.190 111.520 ;
        RECT 1.810 103.680 1440.190 108.000 ;
      LAYER Pwell ;
        RECT 1.810 100.160 161.150 103.680 ;
      LAYER Nwell ;
        RECT 161.150 100.160 1440.190 103.680 ;
        RECT 1.810 95.840 1440.190 100.160 ;
      LAYER Pwell ;
        RECT 1.810 92.320 161.150 95.840 ;
      LAYER Nwell ;
        RECT 161.150 92.320 1440.190 95.840 ;
        RECT 1.810 88.000 1440.190 92.320 ;
      LAYER Pwell ;
        RECT 1.810 84.480 161.150 88.000 ;
      LAYER Nwell ;
        RECT 161.150 84.480 1440.190 88.000 ;
        RECT 1.810 80.160 1440.190 84.480 ;
      LAYER Pwell ;
        RECT 1.810 76.640 161.150 80.160 ;
      LAYER Nwell ;
        RECT 161.150 76.640 1440.190 80.160 ;
        RECT 1.810 72.320 1440.190 76.640 ;
      LAYER Pwell ;
        RECT 1.810 68.800 161.150 72.320 ;
      LAYER Nwell ;
        RECT 161.150 68.800 1440.190 72.320 ;
        RECT 1.810 64.480 1440.190 68.800 ;
      LAYER Pwell ;
        RECT 1.810 60.960 161.150 64.480 ;
      LAYER Nwell ;
        RECT 161.150 60.960 1440.190 64.480 ;
        RECT 1.810 56.640 1440.190 60.960 ;
      LAYER Pwell ;
        RECT 1.810 53.120 161.150 56.640 ;
      LAYER Nwell ;
        RECT 161.150 53.120 1440.190 56.640 ;
        RECT 1.810 48.800 1440.190 53.120 ;
      LAYER Pwell ;
        RECT 1.810 45.280 161.150 48.800 ;
      LAYER Nwell ;
        RECT 161.150 45.280 1440.190 48.800 ;
        RECT 1.810 40.960 1440.190 45.280 ;
      LAYER Pwell ;
        RECT 1.810 37.440 161.150 40.960 ;
      LAYER Nwell ;
        RECT 161.150 37.440 1440.190 40.960 ;
        RECT 1.810 33.120 1440.190 37.440 ;
      LAYER Pwell ;
        RECT 1.810 29.600 161.150 33.120 ;
      LAYER Nwell ;
        RECT 161.150 29.600 1440.190 33.120 ;
        RECT 1.810 25.280 1440.190 29.600 ;
      LAYER Pwell ;
        RECT 1.810 21.760 161.150 25.280 ;
      LAYER Nwell ;
        RECT 161.150 21.760 1440.190 25.280 ;
        RECT 1.810 17.440 1440.190 21.760 ;
      LAYER Pwell ;
        RECT 1.810 13.920 161.150 17.440 ;
      LAYER Nwell ;
        RECT 161.150 13.920 1440.190 17.440 ;
        RECT 1.810 9.600 1440.190 13.920 ;
      LAYER Pwell ;
        RECT 1.810 7.410 161.150 9.600 ;
      LAYER Nwell ;
        RECT 161.150 7.410 1440.190 9.600 ;
        RECT 1.810 4.170 1440.190 7.410 ;
      LAYER Metal1 ;
        RECT 2.240 4.300 1439.760 733.340 ;
      LAYER Metal2 ;
        RECT 20.800 0.680 1361.220 736.310 ;
      LAYER Metal3 ;
        RECT 20.750 1.380 1361.270 736.260 ;
      LAYER Metal4 ;
        RECT 33.210 735.660 39.590 736.310 ;
        RECT 40.490 735.660 46.870 736.310 ;
        RECT 47.770 735.660 54.150 736.310 ;
        RECT 55.050 735.660 61.430 736.310 ;
        RECT 62.330 735.660 68.710 736.310 ;
        RECT 69.610 735.660 75.990 736.310 ;
        RECT 76.890 735.660 83.270 736.310 ;
        RECT 84.170 735.660 90.550 736.310 ;
        RECT 91.450 735.660 97.830 736.310 ;
        RECT 98.730 735.660 105.110 736.310 ;
        RECT 106.010 735.660 112.390 736.310 ;
        RECT 113.290 735.660 119.670 736.310 ;
        RECT 120.570 735.660 126.950 736.310 ;
        RECT 127.850 735.660 134.230 736.310 ;
        RECT 135.130 735.660 141.510 736.310 ;
        RECT 142.410 735.660 148.790 736.310 ;
        RECT 149.690 735.660 156.070 736.310 ;
        RECT 156.970 735.660 163.350 736.310 ;
        RECT 164.250 735.660 170.630 736.310 ;
        RECT 171.530 735.660 177.910 736.310 ;
        RECT 178.810 735.660 185.190 736.310 ;
        RECT 186.090 735.660 192.470 736.310 ;
        RECT 193.370 735.660 199.750 736.310 ;
        RECT 200.650 735.660 207.030 736.310 ;
        RECT 207.930 735.660 214.310 736.310 ;
        RECT 215.210 735.660 221.590 736.310 ;
        RECT 222.490 735.660 228.870 736.310 ;
        RECT 229.770 735.660 236.150 736.310 ;
        RECT 237.050 735.660 243.430 736.310 ;
        RECT 244.330 735.660 250.710 736.310 ;
        RECT 251.610 735.660 257.990 736.310 ;
        RECT 258.890 735.660 265.270 736.310 ;
        RECT 266.170 735.660 272.550 736.310 ;
        RECT 273.450 735.660 279.830 736.310 ;
        RECT 280.730 735.660 287.110 736.310 ;
        RECT 288.010 735.660 294.390 736.310 ;
        RECT 295.290 735.660 301.670 736.310 ;
        RECT 302.570 735.660 308.950 736.310 ;
        RECT 309.850 735.660 316.230 736.310 ;
        RECT 317.130 735.660 323.510 736.310 ;
        RECT 324.410 735.660 330.790 736.310 ;
        RECT 331.690 735.660 338.070 736.310 ;
        RECT 338.970 735.660 1319.620 736.310 ;
        RECT 32.620 733.640 1319.620 735.660 ;
        RECT 32.620 15.330 70.340 733.640 ;
        RECT 74.140 15.330 75.240 733.640 ;
        RECT 79.040 15.330 120.340 733.640 ;
        RECT 124.140 15.330 125.240 733.640 ;
        RECT 129.040 667.380 1319.620 733.640 ;
        RECT 129.040 15.330 184.180 667.380 ;
        RECT 186.380 15.330 187.480 667.380 ;
        RECT 189.680 15.330 259.780 667.380 ;
        RECT 261.980 15.330 263.080 667.380 ;
        RECT 265.280 15.330 359.780 667.380 ;
        RECT 361.980 15.330 363.080 667.380 ;
        RECT 365.280 15.330 459.780 667.380 ;
        RECT 461.980 15.330 463.080 667.380 ;
        RECT 465.280 15.330 511.780 667.380 ;
        RECT 513.980 15.330 515.080 667.380 ;
        RECT 517.280 15.330 611.780 667.380 ;
        RECT 613.980 15.330 615.080 667.380 ;
        RECT 617.280 15.330 711.780 667.380 ;
        RECT 713.980 15.330 715.080 667.380 ;
        RECT 717.280 15.330 763.780 667.380 ;
        RECT 765.980 15.330 767.080 667.380 ;
        RECT 769.280 15.330 863.780 667.380 ;
        RECT 865.980 15.330 867.080 667.380 ;
        RECT 869.280 15.330 963.780 667.380 ;
        RECT 965.980 15.330 967.080 667.380 ;
        RECT 969.280 15.330 1015.780 667.380 ;
        RECT 1017.980 15.330 1019.080 667.380 ;
        RECT 1021.280 15.330 1115.780 667.380 ;
        RECT 1117.980 15.330 1119.080 667.380 ;
        RECT 1121.280 15.330 1215.780 667.380 ;
        RECT 1217.980 15.330 1219.080 667.380 ;
        RECT 1221.280 15.330 1267.780 667.380 ;
        RECT 1269.980 15.330 1271.080 667.380 ;
        RECT 1273.280 15.330 1319.620 667.380 ;
  END
END tt_um_fabulous_gf_0p3
END LIBRARY

